PROGRAM p00_true_false
VAR
	M0: BOOL;
	M1: BOOL;
END_VAR

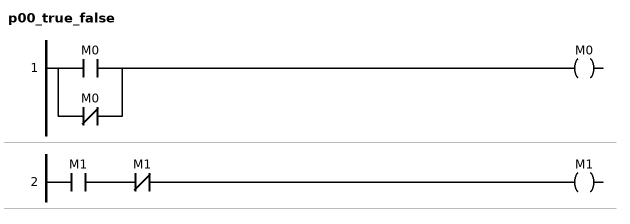
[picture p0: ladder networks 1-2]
// NETWORK 1
M0 := M0 OR NOT M0;

// NETWORK 2
M1 := M1 AND NOT M1;

END_PROGRAM
